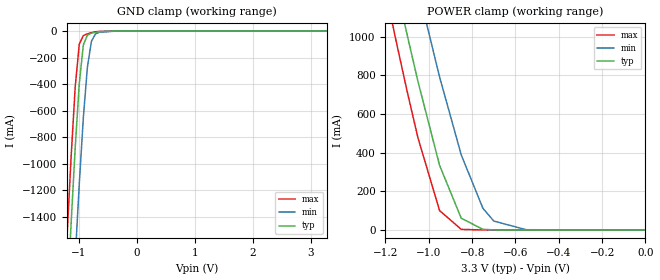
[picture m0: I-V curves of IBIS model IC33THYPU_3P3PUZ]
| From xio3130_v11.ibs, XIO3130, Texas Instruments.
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|   Model IC33THYPU_3P3PUZ
[Model]   IC33THYPU_3P3PUZ
Model_type   Input
Polarity   Non-Inverting
Vinh = 2.31V
Vinl = 0.99V
|   typ   min   max
C_comp   1.73928pF   1.8860pF   1.6401pF
[Model Spec]
|   typ   min   max
Vinh   2.31V   2.10V   2.52V
Vinl   0.99V   0.90V   1.08V
[Temperature Range]   25   125   -40
[Voltage Range]   3.30V   3.00V   3.60V
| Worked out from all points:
|   GND clamp passes 1 mA (typ) near -0.55 V on its own axis
|   POWER clamp passes 1 mA (typ) near -0.71 V on its own axis
|(Vdd votage range)  (Vdd votage range)   1.50V   1.35V   1.65V
| (Process strength)   nominal   weak   strong
[GND_clamp]
| voltage   I(typ)   I(min)   I(max)
-3.3V     -22.44A    -23.22A    -22A
-1.2V     -2.056A    -2.93A     -1.544A
-1.13V    -1.448A    -2.312A    -946.6mA
-1.06V    -880.2mA   -1.716A    -422mA
-990mV    -397.7mA   -1.154A    -98.88mA
-920mV    -105.5mA   -654.7mA   -33.64mA
-850mV    -30.1mA    -272.5mA   -21.05mA
-780mV    -16.02mA   -76.09mA   -12.17mA
-710mV    -8.881mA   -21.66mA   -5.484mA
-640mV    -3.975mA   -8.88mA    -1.645mA
-360mV    -5.768uA   -101.8uA   -203.4nA
3.28V     331.3pA    679.2nA    97.83pA
[POWER_clamp]
| voltage   I(typ)   I(min)   I(max)
-3.3V     13.18A     13.26A     13.32A
-1.25V    1.778A     2.241A     1.508A
-1.2V     1.518A     1.988A     1.238A
-1.15V    1.262A     1.738A     974.1mA
-1.1V     1.011A     1.492A     718.6mA
-1.05V    769.2mA    1.251A     477.2mA
-950mV    334.1mA    791.5mA    100.2mA
-850mV    60.69mA    388.3mA    3.129mA
-750mV    3.199mA    112.3mA    28.05uA
-700mV    511.3uA    46.13mA    3.229uA
-550mV    1.956uA    1.225mA    61.72nA
0V        336.5pA    63.37nA    111.7pA
